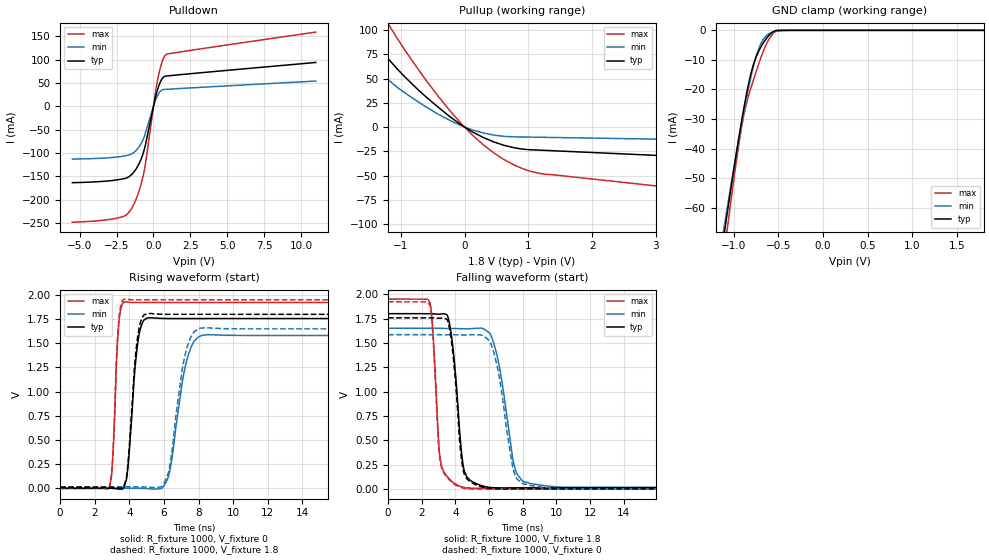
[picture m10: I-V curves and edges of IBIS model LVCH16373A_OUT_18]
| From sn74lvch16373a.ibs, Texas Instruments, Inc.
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[Model]   LVCH16373A_OUT_18
Model_type  3-state
Enable   Active-Low
Vref =   0
Rref =   1000
Cref =   30p
Vmeas =   0.9
| variable   typ   min   max
C_comp   5.29pF   4.86pF   6.09pF
| C_pullup   13.48pF   4.54pF   30.29pF
| C_pulldown   7.86pF   1.15pF   9.53pF
| C_tri-state   5.29pF   4.86pF   6.09pF
[Temperature Range]   40   100   -40
| Ambient temperature   25   85   -40
[Voltage range]   1.8   1.65   1.95
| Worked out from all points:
|   slope of the pulldown table from 0 to 0.27 V, typ, clamps not added: 7.65 ohm
|   slope of the pullup table from 0 to 0.27 V, typ, clamps not added: 27.1 ohm
|   GND clamp passes 1 mA (typ) near -0.58 V on its own axis
|   rising waveform, R_fixture 1000, V_fixture 0: 20-80 % time 437ps typ, 774ps min, 263ps max; typ from 0 V to 1.76 V
|   falling waveform, R_fixture 1000, V_fixture 1.8: 20-80 % time 511ps typ, 847ps min, 358ps max; typ from 1.8 V to 0.012 V
|   rising waveform, R_fixture 1000, V_fixture 1.8: 20-80 % time 423ps typ, 724ps min, 260ps max; typ from 0.012 V to 1.8 V
|   falling waveform, R_fixture 1000, V_fixture 0: 20-80 % time 490ps typ, 846ps min, 351ps max; typ from 1.76 V to 0 V
[GND Clamp]
| LVCH16373A_OUT_18
|   Voltage   I(typ)   I(min)   I(max)
-5.5V     -1.136A    -1.03A     -1.309A
-1.11V    -69.33mA   -66.78mA   -75.88mA
-1.08V    -63.12mA   -61.16mA   -68.74mA
-1.05V    -56.99mA   -55.61mA   -61.72mA
-965mV    -40.27mA   -40.41mA   -42.88mA
-905mV    -29.31mA   -30.29mA   -31.46mA
-805mV    -14.26mA   -15.32mA   -19.12mA
-745mV    -8.625mA   -8.347mA   -13.5mA
-685mV    -5.028mA   -3.805mA   -8.274mA
-615mV    -1.996mA   -1.316mA   -3.491mA
-540mV    -171.5uA   -477.2uA   -522.1uA
1.8V      37.82pA    12.26nA    -2.547nA
[Pulldown]
| LVCH16373A_OUT_18
|   Voltage   I(typ)   I(min)   I(max)
-5.5V     -163.6mA   -112.9mA   -248.3mA
-2.09V    -155.5mA   -106.9mA   -236.8mA
-1.755V   -152.5mA   -104.9mA   -230.2mA
-1.43V    -144.6mA   -100.8mA   -216mA
-1.035V   -126.5mA   -89.23mA   -186.9mA
-690mV    -99.77mA   -70mA      -147.4mA
-520mV    -79.21mA   -54.46mA   -118mA
70mV      10.47mA    6.993mA    15.91mA
275mV     35.8mA     23.13mA    55.48mA
565mV     58.22mA    35.03mA    93.73mA
855mV     65.08mA    36.56mA    111.2mA
11V       94.21mA    54.33mA    159.3mA
[Pullup]
| LVCH16373A_OUT_18
|   Voltage   I(typ)   I(min)   I(max)
-5.5V     45.13mA    14.9mA     119.9mA
-3.68V    60.19mA    18.01mA    194.1mA
-3.145V   106.6mA    21.79mA    315.9mA
-2.915V   190.7mA    26.02mA    295.9mA
-2.74V    184.6mA    37.5mA     278.6mA
-2.59V    176mA      115.3mA    263mA
-2.22V    150.5mA    107.7mA    222.7mA
-1.72V    112mA      80.42mA    165.8mA
-1.22V    72.11mA    50.05mA    108.9mA
125mV     -4.951mA   -2.896mA   -8.274mA
1.14V     -23.61mA   -10.4mA    -47.22mA
11V       -53.91mA   -20.99mA   -120.6mA
[Ramp]
| LVCH16373A_OUT_18
| variable   typ   min   max
dV/dt_r   1.06/4.71E-10   0.96/8.53E-10   1.16/2.81E-10
dV/dt_f   1.07/5.29E-10   0.98/8.69E-10   1.17/3.75E-10
R_load = 1000
[Rising Waveform]
| LVCH16373A_OUT_18
R_fixture =   1000
C_fixture =   0
L_fixture =   0
V_fixture =   0
V_fixture_min = 0
V_fixture_max = 0
|   Time   V(typ)   V(min)   V(max)
0s        561.2pV    2.27nV     19.09nV
2.835ns   1.324mV    141.1uV    3.906mV
3.38ns    -7.434mV   1.317mV    1.674V
3.715ns   26.26mV    1.125mV    1.928V
4.485ns   1.501V     470.3uV    1.921V
5.04ns    1.762V     -2.596mV   1.922V
6.27ns    1.756V     124.1mV    1.922V
7.255ns   1.756V     1.277V     1.922V
8.165ns   1.756V     1.581V     1.922V
40ns      1.756V     1.581V     1.922V
[Falling Waveform]
| LVCH16373A_OUT_18
R_fixture =   1000
C_fixture =   0
L_fixture =   0
V_fixture =   1.8
V_fixture_min = 1.65
V_fixture_max = 1.95
|   Time   V(typ)   V(min)   V(max)
0s        1.8V       1.65V      1.95V
2.5ns     1.799V     1.65V      1.908V
3.05ns    1.795V     1.65V      375.6mV
3.515ns   1.785V     1.648V     126.3mV
3.89ns    1.389V     1.648V     64mV
4.425ns   279.8mV    1.645V     18.89mV
6.135ns   13.85mV    1.564V     7.859mV
7.455ns   11.49mV    267.7mV    8.296mV
8.105ns   11.49mV    70.7mV     8.316mV
40ns      11.54mV    15.75mV    8.265mV
[Rising Waveform]
| LVCH16373A_OUT_18
R_fixture =   1000
C_fixture =   0
L_fixture =   0
V_fixture =   1.8
V_fixture_min = 1.65
V_fixture_max = 1.95
|   Time   V(typ)   V(min)   V(max)
0s        11.51mV    15.68mV    8.257mV
2.835ns   12.65mV    15.84mV    12.8mV
3.375ns   4.35mV     16.78mV    1.707V
3.71ns    38.78mV    16.44mV    1.958V
4.46ns    1.54V      15.62mV    1.95V
5.02ns    1.808V     12.86mV    1.95V
6.25ns    1.8V       158.1mV    1.95V
7.2ns     1.8V       1.363V     1.95V
8.105ns   1.8V       1.657V     1.95V
40ns      1.8V       1.65V      1.95V
[Falling Waveform]
| LVCH16373A_OUT_18
R_fixture =   1000
C_fixture =   0
L_fixture =   0
V_fixture =   0
V_fixture_min = 0
V_fixture_max = 0
|   Time   V(typ)   V(min)   V(max)
0s        1.758V     1.585V     1.922V
2.5ns     1.757V     1.585V     1.878V
3.045ns   1.754V     1.584V     355.3mV
3.515ns   1.738V     1.583V     116.4mV
3.865ns   1.366V     1.583V     58.23mV
4.425ns   230mV      1.582V     10.49mV
6.085ns   2.709mV    1.5V       -377.4uV
7.405ns   59.19uV    223.9mV    38.7uV
8.085ns   -5.318uV   47.7mV     57.51uV
40ns      20.9uV     68.86uV    8.072uV
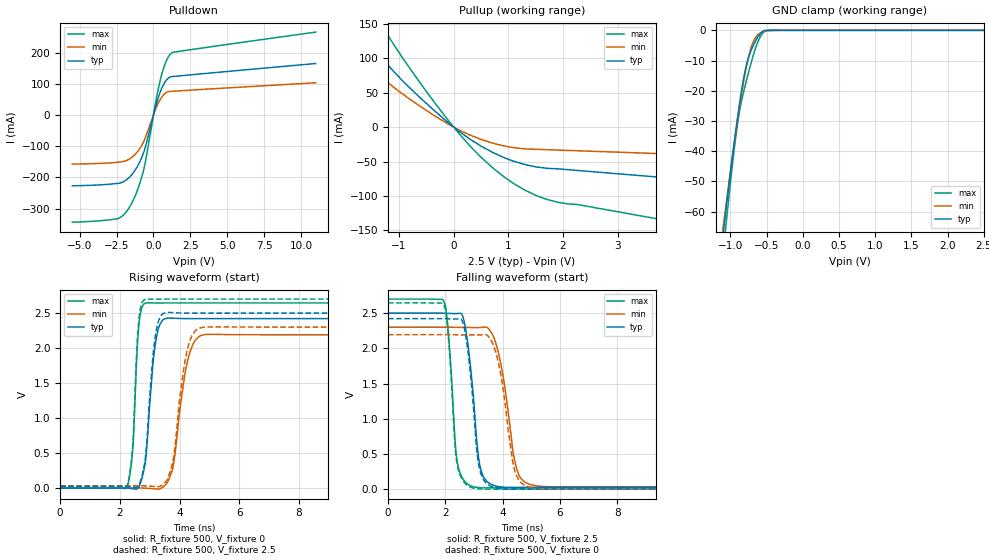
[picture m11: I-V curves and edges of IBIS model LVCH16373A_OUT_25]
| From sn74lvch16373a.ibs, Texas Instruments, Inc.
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[Model]   LVCH16373A_OUT_25
Model_type  3-state
Enable   Active-Low
Vref =   0
Rref =   500
Cref =   30p
Vmeas =   1.25
| variable   typ   min   max
C_comp   5.05pF   4.53pF   6.02pF
| C_pullup   5.89pF   4.21pF   7.82pF
| C_pulldown   7.65pF   6.83pF   8.70pF
| C_tri-state   5.05pF   4.53pF   6.02pF
[Temperature Range]   40   100   -40
| Ambient temperature   25   85   -40
[Voltage range]   2.5   2.3   2.7
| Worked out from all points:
|   slope of the pulldown table from 0 to 0.375 V, typ, clamps not added: 6 ohm
|   slope of the pullup table from 0 to 0.375 V, typ, clamps not added: 17.5 ohm
|   GND clamp passes 1 mA (typ) near -0.58 V on its own axis
|   rising waveform, R_fixture 500, V_fixture 0: 20-80 % time 270ps typ, 404ps min, 172ps max; typ from 0 V to 2.42 V
|   falling waveform, R_fixture 500, V_fixture 2.5: 20-80 % time 335ps typ, 479ps min, 247ps max; typ from 2.5 V to 0.025 V
|   rising waveform, R_fixture 500, V_fixture 2.5: 20-80 % time 261ps typ, 383ps min, 171ps max; typ from 0.025 V to 2.5 V
|   falling waveform, R_fixture 500, V_fixture 0: 20-80 % time 321ps typ, 462ps min, 241ps max; typ from 2.42 V to 0 V
[GND Clamp]
| LVCH16373A_OUT_25
|   Voltage   I(typ)   I(min)   I(max)
-5.5V     -1.136A    -1.03A     -1.309A
-1.105V   -68.29mA   -65.84mA   -74.68mA
-1.075V   -62.09mA   -60.23mA   -67.56mA
-1.045V   -55.98mA   -54.7mA    -60.56mA
-960mV    -39.32mA   -39.55mA   -41.85mA
-905mV    -29.31mA   -30.29mA   -31.46mA
-805mV    -14.26mA   -15.32mA   -19.12mA
-750mV    -8.994mA   -8.844mA   -13.96mA
-690mV    -5.285mA   -4.084mA   -8.679mA
-610mV    -1.821mA   -1.216mA   -3.219mA
-535mV    -123.1uA   -445.7uA   -414.9uA
2.5V      50.37pA    32.08nA    -2.817nA
[Pulldown]
| LVCH16373A_OUT_25
|   Voltage   I(typ)   I(min)   I(max)
-5.5V     -227.2mA   -157.4mA   -343.8mA
-2.45V    -219.5mA   -151.7mA   -332.8mA
-2.015V   -213.6mA   -149mA     -319.9mA
-1.585V   -197.6mA   -139.7mA   -292.7mA
-1.085V   -164.7mA   -118mA     -241.1mA
-650mV    -118.1mA   -84.14mA   -173.1mA
-495mV    -93.16mA   -65.54mA   -137.4mA
190mV     34.44mA    23.84mA    51.4mA
550mV     84.2mA     56.6mA     128mA
880mV     112mA      72.43mA    174.5mA
1.21V     122.9mA    75.8mA     198.2mA
11V       165.1mA    103.4mA    265.9mA
[Pullup]
| LVCH16373A_OUT_25
|   Voltage   I(typ)   I(min)   I(max)
-5.5V     148.2mA    57.93mA    351mA
-4.045V   321.7mA    79.05mA    492.8mA
-3.805V   313.1mA    98.6mA     466.4mA
-3.695V   306.5mA    139.9mA    453.7mA
-3.62V    301.5mA    170.1mA    444.9mA
-2.485V   207.8mA    154.2mA    301.6mA
-2.175V   179.6mA    133.2mA    260.8mA
-1.32V    100.5mA    72.92mA    147.9mA
510mV     -27.96mA   -18.07mA   -44.43mA
1.92V     -60.68mA   -33.35mA   -109.4mA
4.48V     -77.36mA   -40.45mA   -143.9mA
11V       -121.1mA   -58.83mA   -239.8mA
[Ramp]
| LVCH16373A_OUT_25
| variable   typ   min   max
dV/dt_r   1.47/2.90E-10   1.33/4.37E-10   1.59/1.78E-10
dV/dt_f   1.48/3.45E-10   1.36/4.99E-10   1.61/2.55E-10
R_load = 500
[Rising Waveform]
| LVCH16373A_OUT_25
R_fixture =   500
C_fixture =   0
L_fixture =   0
V_fixture =   0
V_fixture_min = 0
V_fixture_max = 0
|   Time   V(typ)   V(min)   V(max)
0s        617.4pV    1.958nV    18.26nV
2.24ns    251.5uV    567.4uV    9.298mV
2.44ns    -9.383mV   1.735mV    601.8mV
2.64ns    20.87mV    2.49mV     2.338V
2.9ns     575mV      -2.445mV   2.647V
3.335ns   2.331V     -10.99mV   2.645V
3.775ns   2.428V     286.4mV    2.645V
4.33ns    2.421V     1.917V     2.645V
4.88ns    2.421V     2.195V     2.645V
40ns      2.421V     2.191V     2.645V
[Falling Waveform]
| LVCH16373A_OUT_25
R_fixture =   500
C_fixture =   0
L_fixture =   0
V_fixture =   2.5
V_fixture_min = 2.3
V_fixture_max = 2.7
|   Time   V(typ)   V(min)   V(max)
0s        2.5V       2.3V       2.7V
1.95ns    2.499V     2.3V       2.665V
2.42ns    2.495V     2.299V     374.6mV
2.7ns     2.295V     2.297V     99.25mV
3.035ns   1.016V     2.294V     26.99mV
3.435ns   115.4mV    2.303V     18.16mV
3.915ns   31.67mV    1.824V     18.51mV
4.49ns    24.61mV    289.3mV    18.59mV
5.185ns   25.29mV    44.08mV    18.61mV
40ns      25.47mV    33.5mV     18.58mV
[Rising Waveform]
| LVCH16373A_OUT_25
R_fixture =   500
C_fixture =   0
L_fixture =   0
V_fixture =   2.5
V_fixture_min = 2.3
V_fixture_max = 2.7
|   Time   V(typ)   V(min)   V(max)
0s        25.45mV    33.45mV    18.57mV
2.24ns    25.45mV    33.96mV    28.63mV
2.435ns   16.44mV    34.9mV     634.5mV
2.635ns   44.9mV     35.4mV     2.398V
2.88ns    541.5mV    30.82mV    2.699V
3.32ns    2.417V     21.83mV    2.7V
3.77ns    2.507V     364.6mV    2.7V
4.3ns     2.5V       2.041V     2.7V
4.83ns    2.5V       2.299V     2.7V
40ns      2.5V       2.3V       2.7V
[Falling Waveform]
| LVCH16373A_OUT_25
R_fixture =   500
C_fixture =   0
L_fixture =   0
V_fixture =   0
V_fixture_min = 0
V_fixture_max = 0
|   Time   V(typ)   V(min)   V(max)
0s        2.422V     2.194V     2.646V
1.95ns    2.421V     2.194V     2.61V
2.41ns    2.417V     2.193V     354.3mV
2.7ns     2.207V     2.192V     77.12mV
3.035ns   866.5mV    2.19V      7.907mV
3.435ns   81.79mV    2.194V     -537.1uV
3.88ns    5.998mV    1.743V     -25.05uV
4.445ns   -430.4uV   233.1mV    25.63uV
5.155ns   -76.01uV   9.286mV    36.88uV
40ns      18.35uV    47.83uV    6.244uV
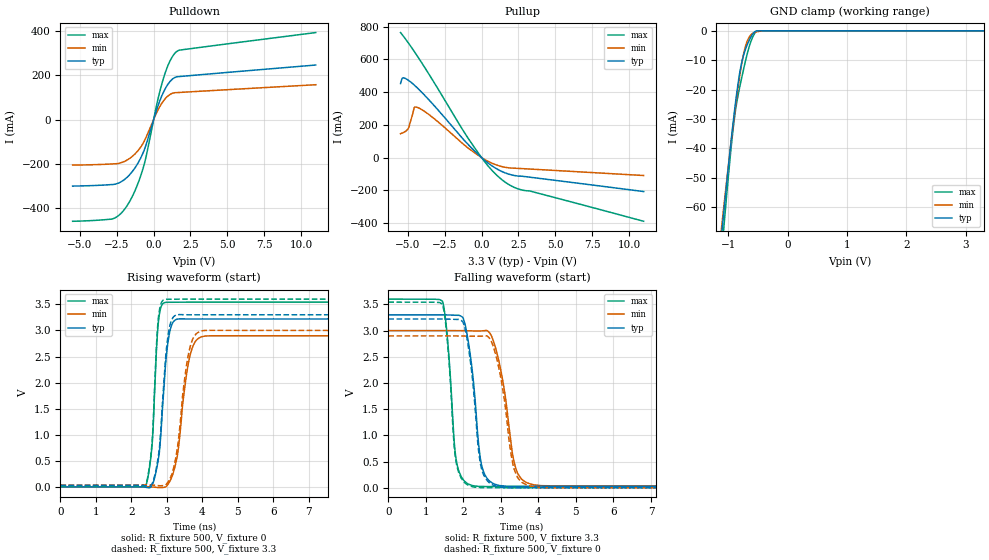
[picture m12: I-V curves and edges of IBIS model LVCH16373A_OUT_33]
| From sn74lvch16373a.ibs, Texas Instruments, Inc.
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[Model]   LVCH16373A_OUT_33
Model_type  3-state
Enable   Active-Low
Vref =   0
Rref =   500
Cref =   50p
Vmeas =   1.5
| variable   typ   min   max
C_comp   4.83pF   4.36pF   6.03pF
| C_pullup   6.00pF   4.37pF   8.37pF
| C_pulldown   6.70pF   4.32pF   7.76pF
| C_tri-state   4.83pF   4.36pF   6.03pF
[Temperature Range]   40   100   -40
| Ambient temperature   25   85   -40
[Voltage range]   3.3   3   3.6
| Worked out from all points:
|   slope of the pulldown table from 0 to 0.495 V, typ, clamps not added: 5.09 ohm
|   slope of the pullup table from 0 to 0.495 V, typ, clamps not added: 13.3 ohm
|   GND clamp passes 1 mA (typ) near -0.58 V on its own axis
|   rising waveform, R_fixture 500, V_fixture 0: 20-80 % time 210ps typ, 301ps min, 155ps max; typ from 0 V to 3.22 V
|   falling waveform, R_fixture 500, V_fixture 3.3: 20-80 % time 268ps typ, 365ps min, 201ps max; typ from 3.3 V to 0.029 V
|   rising waveform, R_fixture 500, V_fixture 3.3: 20-80 % time 208ps typ, 303ps min, 154ps max; typ from 0.029 V to 3.3 V
|   falling waveform, R_fixture 500, V_fixture 0: 20-80 % time 261ps typ, 349ps min, 197ps max; typ from 3.22 V to 0 V
[GND Clamp]
| LVCH16373A_OUT_33
|   Voltage   I(typ)   I(min)   I(max)
-5.5V     -1.136A    -1.03A     -1.309A
-1.115V   -70.38mA   -67.72mA   -77.08mA
-1.08V    -63.12mA   -61.16mA   -68.74mA
-1.05V    -56.99mA   -55.61mA   -61.72mA
-965mV    -40.27mA   -40.41mA   -42.88mA
-900mV    -28.44mA   -29.48mA   -30.63mA
-795mV    -13.12mA   -14.02mA   -18.16mA
-730mV    -7.596mA   -6.963mA   -12.14mA
-675mV    -4.532mA   -3.295mA   -7.486mA
-590mV    -1.187mA   -895.4uA   -2.233mA
-520mV    -43.08uA   -358.4uA   -168.9uA
3.3V      64.68pA    54.7nA     -2.347nA
[Pulldown]
| LVCH16373A_OUT_33
|   Voltage   I(typ)   I(min)   I(max)
-5.5V     -300mA     -205.4mA   -458.6mA
-2.77V    -292.8mA   -200mA     -447.1mA
-2.245V   -281.8mA   -195.3mA   -424.8mA
-1.725V   -255.2mA   -179.5mA   -380mA
-1.165V   -207.3mA   -148mA     -304.8mA
-665mV    -141.6mA   -101mA     -207.9mA
-495mV    -109.4mA   -77.12mA   -161.5mA
255mV     54.31mA    37.86mA    80.86mA
710mV     129mA      87.77mA    195.2mA
1.135V    173mA      114mA      267.3mA
1.56V     192.2mA    121.2mA    306.1mA
11V       245.5mA    156.8mA    391.8mA
[Pullup]
| LVCH16373A_OUT_33
|   Voltage   I(typ)   I(min)   I(max)
-5.5V     452.5mA    146.1mA    764mA
-5.36V    486.1mA    150.8mA    748mA
-4.98V    473.1mA    177.1mA    701.9mA
-4.915V   468.9mA    190.3mA    693.7mA
-4.575V   443.6mA    303.9mA    649.3mA
-4.37V    426.5mA    306.9mA    621.8mA
-3.355V   331.3mA    247.7mA    478.2mA
-595mV    51.37mA    37.19mA    76.04mA
480mV     -36.08mA   -24.78mA   -55.24mA
1.435V    -87.51mA   -56.43mA   -139.2mA
2.59V     -113.6mA   -66.71mA   -194.7mA
11V       -207.7mA   -109.8mA   -389.6mA
[Ramp]
| LVCH16373A_OUT_33
| variable   typ   min   max
dV/dt_r   1.94/2.19E-10   1.75/3.08E-10   2.13/1.58E-10
dV/dt_f   1.96/2.75E-10   1.78/3.73E-10   2.15/2.09E-10
R_load = 500
[Rising Waveform]
| LVCH16373A_OUT_33
R_fixture =   500
C_fixture =   0
L_fixture =   0
V_fixture =   0
V_fixture_min = 0
V_fixture_max = 0
|   Time   V(typ)   V(min)   V(max)
0s        761.6pV    1.869nV    19.44nV
2.395ns   -5.831mV   1.874mV    1.116mV
2.59ns    42.26mV    -1.077mV   863mV
2.755ns   510.8mV    -12.06mV   3.12V
2.955ns   2.277V     -3.892mV   3.537V
3.095ns   3.017V     123.2mV    3.54V
3.295ns   3.217V     594mV      3.541V
3.665ns   3.22V      2.552V     3.542V
4.09ns    3.22V      2.893V     3.542V
40ns      3.22V      2.896V     3.542V
[Falling Waveform]
| LVCH16373A_OUT_33
R_fixture =   500
C_fixture =   0
L_fixture =   0
V_fixture =   3.3
V_fixture_min = 3
V_fixture_max = 3.6
|   Time   V(typ)   V(min)   V(max)
0s        3.3V       3V         3.6V
1.44ns    3.3V       3V         3.564V
1.82ns    3.292V     2.999V     483.2mV
2.055ns   3.085V     2.997V     108.8mV
2.3ns     1.779V     2.993V     33.52mV
2.63ns    180.4mV    2.999V     22.75mV
2.97ns    41.36mV    2.339V     21.55mV
3.41ns    27.33mV    343.3mV    21.29mV
4.005ns   28.39mV    44.01mV    21.19mV
40ns      28.6mV     36.92mV    21.11mV
[Rising Waveform]
| LVCH16373A_OUT_33
R_fixture =   500
C_fixture =   0
L_fixture =   0
V_fixture =   3.3
V_fixture_min = 3
V_fixture_max = 3.6
|   Time   V(typ)   V(min)   V(max)
0s        28.58mV    36.89mV    21.11mV
2.395ns   22.62mV    38.5mV     22.68mV
2.59ns    73.06mV    35.25mV    921.5mV
2.74ns    502.9mV    25.5mV     3.079V
2.95ns    2.347V     34.2mV     3.595V
3.08ns    3.079V     149.6mV    3.598V
3.26ns    3.295V     594mV      3.599V
3.65ns    3.3V       2.67V      3.6V
4.07ns    3.3V       3V         3.6V
40ns      3.3V       3V         3.6V
[Falling Waveform]
| LVCH16373A_OUT_33
R_fixture =   500
C_fixture =   0
L_fixture =   0
V_fixture =   0
V_fixture_min = 0
V_fixture_max = 0
|   Time   V(typ)   V(min)   V(max)
0s        3.221V     2.898V     3.543V
1.44ns    3.22V      2.898V     3.507V
1.815ns   3.213V     2.897V     456.1mV
2.06ns    2.983V     2.895V     80.37mV
2.31ns    1.542V     2.892V     10.69mV
2.6ns     168.5mV    2.899V     1.875mV
2.945ns   14.06mV    2.288V     465.5uV
3.36ns    -456.6uV   340.7mV    194.3uV
3.925ns   -175.7uV   11.24mV    89.65uV
40ns      18.33uV    32.3uV     5.491uV
